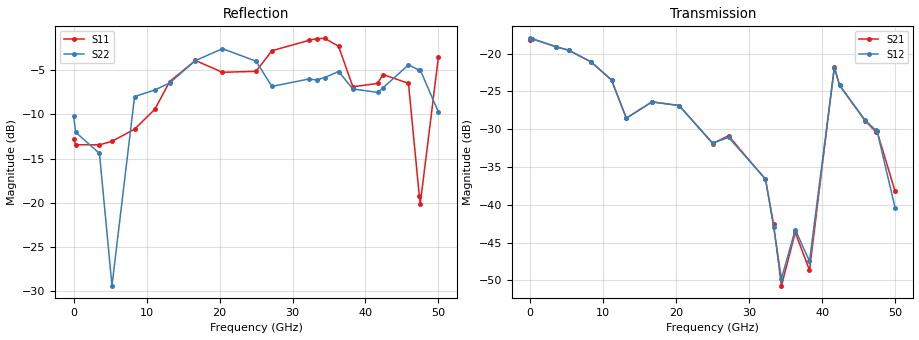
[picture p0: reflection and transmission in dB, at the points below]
!Keysight Technologies,N5245B,MY58422270,A.16.20.02
!Date: Thursday, March 05, 2026 01:19:50
!Correction: S11(C  2-Port  )
!S21(C  2-Port  )
!S12(C  2-Port  )
!S22(C  2-Port  )
!S2P File: Measurements: S11, S21, S12, S22:
# Hz S  dB  R 50
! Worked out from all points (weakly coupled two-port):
!   3201 points, 10 MHz to 50 GHz, reference 50 ohm
!   highest |S21| = -18.04 dB at 275.6 MHz (marker M1); lowest = -50.7 dB at 34.42 GHz (marker M2)
!   lowest |S11| = -20.1 dB at 47.52 GHz (marker M3), VSWR 1.22, Z = 45.9 + j8.57 ohm
!   |S11| at or under -10 dB: start of sweep to 10.19 GHz; 11.35 GHz to 11.93 GHz (580.9 MHz wide, 4.99 % of centre); 46.66 GHz to 48.28 GHz (1.627 GHz wide, 3.43 % of centre)
!   |S22| runs from -29.4 to -2.5 dB; largest |S21 - S12| = 0.0041
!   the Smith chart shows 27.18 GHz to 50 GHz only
!   S11 on the Smith chart (normalised r, x): 27.18 GHz: 0.18, +0.35; 32.24 GHz: 0.41, +1.81; 36.32 GHz: 2.54, -3.50; 42.39 GHz: 1.03, -1.27; 47.38 GHz: 0.83, +0.11; 50 GHz: 0.62, -1.36
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1e7  -12.81 -1.8  -18.26 4.7  -17.98 4.5  -10.21 28.2
2.755719e8  -13.44 -11.9  -18.04 -10.8  -18.04 -10.8  -12.02 -13.8
3.540544e9  -13.45 -93.4  -19.10 -137.2  -19.08 -137.3  -14.41 -167.0
5.25895e9  -13.05 -129.4  -19.54 153.8  -19.55 153.9  -29.39 47.9
8.352081e9  -11.68 174.5  -21.11 24.0  -21.10 24.1  -7.99 -146.0
1.113278e10  -9.43 107.7  -23.50 -83.0  -23.48 -83.1  -7.24 95.7
1.316362e10  -6.29 64.3  -28.55 -142.6  -28.52 -142.6  -6.45 -16.7
1.667854e10  -3.90 -43.8  -26.38 156.1  -26.38 156.5  -3.92 -138.9
2.039655e10  -5.24 -121.0  -26.86 40.2  -26.86 40.4  -2.57 156.1
2.5005e10  -5.13 179.8  -31.89 -64.4  -31.84 -64.8  -3.98 71.6
2.717644e10  -2.80 140.0  -30.86 -112.7  -31.08 -113.6  -6.84 32.4
3.223793e10  -1.63 55.9  -36.64 51.6  -36.57 52.2  -6.00 -101.1
3.334708e10  -1.42 36.1  -42.58 8.5  -42.87 10.2  -6.11 -125.2
3.442499e10  -1.40 16.8  -50.69 -97.7  -49.77 -105.8  -5.83 -147.8
3.631524e10  -2.29 -21.6  -43.65 113.4  -43.27 113.8  -5.15 176.9
3.826797e10  -6.88 -22.3  -48.64 82.0  -47.46 93.1  -7.13 140.3
4.167354e10  -6.50 -52.6  -21.76 -59.5  -21.86 -60.7  -7.51 118.5
4.239215e10  -5.49 -56.6  -24.19 -118.6  -24.18 -118.2  -7.01 114.3
4.589145e10  -6.49 -116.9  -28.89 55.3  -28.80 55.6  -4.40 62.8
4.737552e10  -19.21 142.9  -30.34 3.5  -30.16 5.4  -5.01 42.2
4.751612e10  -20.09 110.7  -30.25 0.9  -30.18 2.6  -5.00 40.6
5e10  -3.52 -65.6  -38.22 -137.4  -40.39 -140.4  -9.74 1.8
